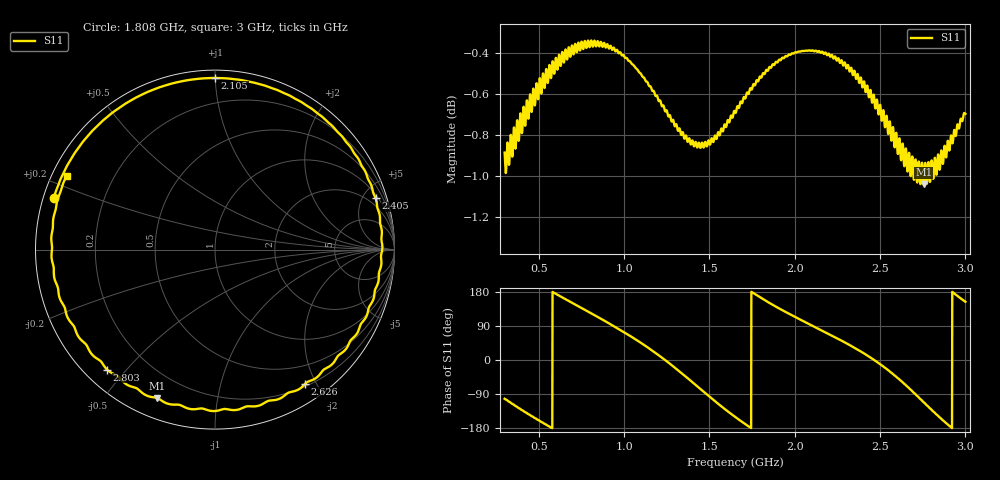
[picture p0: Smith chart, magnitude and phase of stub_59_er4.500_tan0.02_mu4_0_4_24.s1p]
! Chirptenna · simulación 3D de un stub abierto
# HZ S RI R 50
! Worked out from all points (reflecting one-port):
!   2001 points, 300 MHz to 3 GHz, reference 50 ohm
!   lowest |S11| = -1.0 dB at 2.756 GHz (marker M1), VSWR 16.72, Z = 4.38 - j34 ohm
!   phase of S11 starts at -102 deg and turns -824 deg over the sweep
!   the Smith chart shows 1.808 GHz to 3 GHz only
!   S11 on the Smith chart (normalised r, x): 1.808 GHz: 0.03, +0.16; 2.105 GHz: 0.04, +1.00; 2.405 GHz: 1.26, +6.17; 2.626 GHz: 0.23, -1.85; 2.803 GHz: 0.06, -0.44; 3 GHz: 0.04, +0.23
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3e8  -0.1913 -0.8826
3.81e8  -0.5399 -0.7325
4.782e8  -0.8285 -0.417
6.375e8  -0.9242 0.2423
8.1975e8  -0.4807 0.8297
9.75e8  0.1637 0.9411
1.0695e9  0.5587 0.7643
1.16805e9  0.8546 0.3787
1.24095e9  0.9242 -0.00462
1.3125e9  0.8244 -0.3975
1.4043e9  0.4522 -0.7876
1.48125e9  0.00852 -0.907
1.5582e9  -0.4287 -0.8049
1.65e9  -0.8 -0.4621
1.7283e9  -0.9293 -0.0853
1.80795e9  -0.8981 0.286
1.9875e9  -0.4334 0.8506
2.10495e9  -0.00184 0.9563
2.2116e9  0.3889 0.8701
2.325e9  0.7372 0.592
2.40465e9  0.8951 0.2858
2.5248e9  0.8672 -0.3054
2.62605e9  0.5011 -0.7489
2.6625e9  0.2891 -0.8462
2.75565e9  -0.3224 -0.8264
2.8029e9  -0.6011 -0.6687
2.89065e9  -0.8824 -0.1933
3e9  -0.8266 0.4104
